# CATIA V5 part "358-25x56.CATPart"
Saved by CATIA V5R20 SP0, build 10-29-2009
Part number: 358-25X56
Definition: NONE
Nomenclature: 358-25X56
Source: Unknown
Description: 358-25X56
Bounding box of the stored display mesh (mm): x -17 to 39, y -19 to 19, z -19 to 19
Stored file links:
  C:\Users\Utente\Desktop\IO LAVORO\3D X SITO CF\X SITO\PLASTICA\358\358-25x56.CATPart

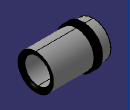
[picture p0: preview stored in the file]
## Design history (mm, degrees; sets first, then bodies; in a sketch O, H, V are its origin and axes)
Body1 "358-25X56" (main body)
  Solid1: solid without history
